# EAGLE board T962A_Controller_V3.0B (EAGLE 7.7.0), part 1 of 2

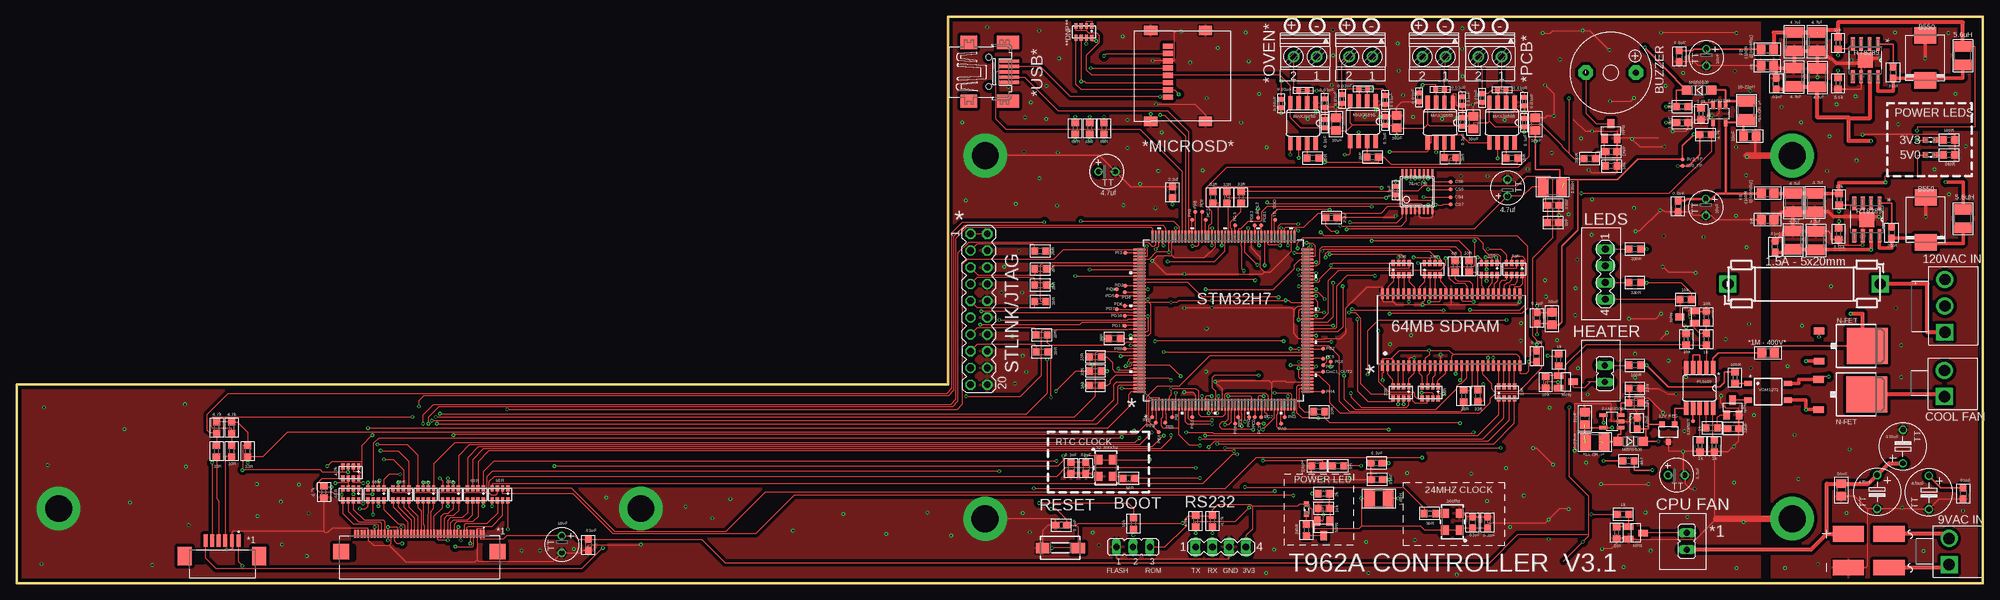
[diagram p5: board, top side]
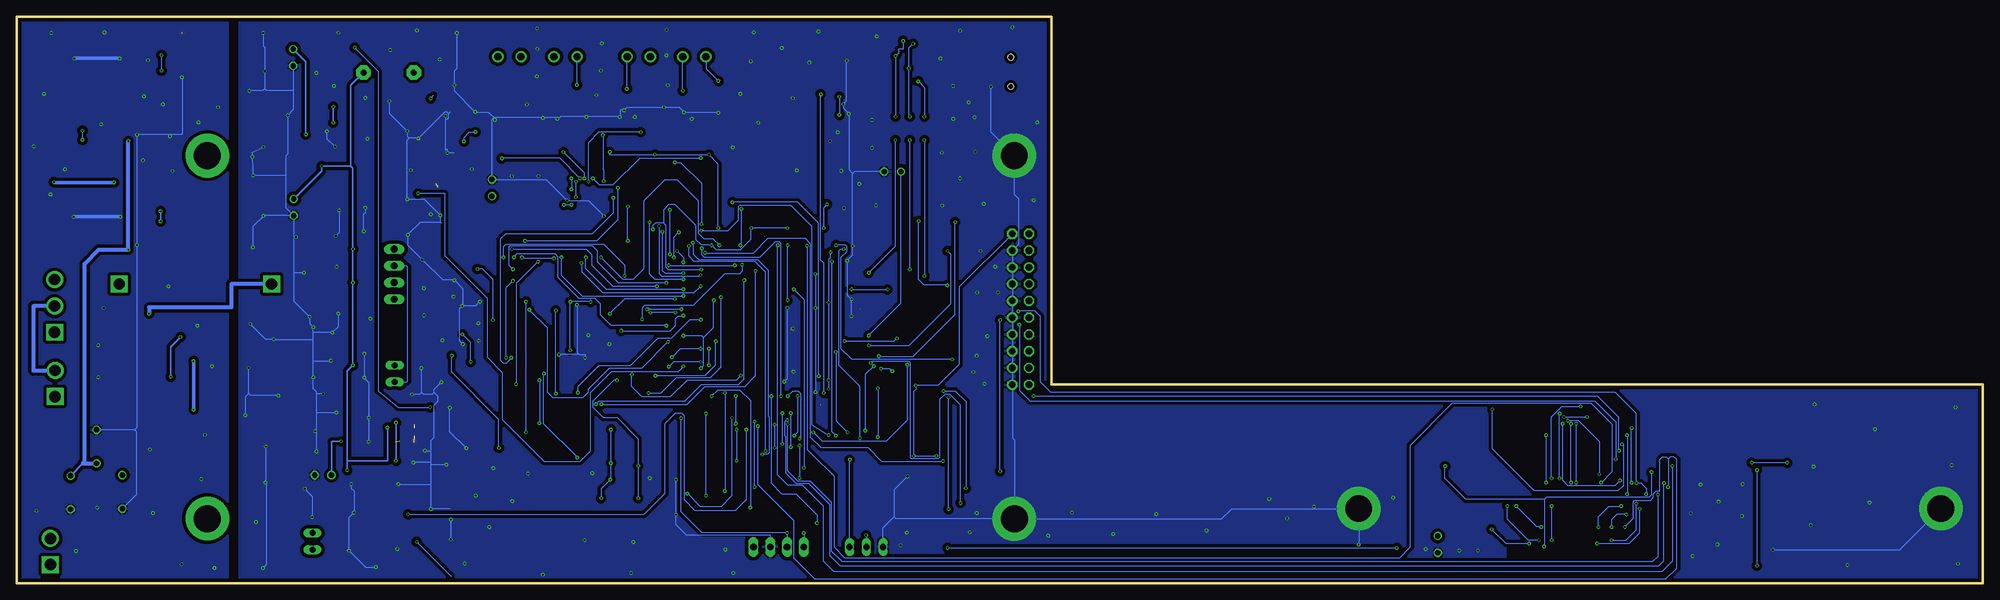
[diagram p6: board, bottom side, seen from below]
Size 297.71 x 85.85 mm. Coordinates in mm from the lower left corner, seen from the top.
Outline: 297.71,0 0,0 0,30.1 141,30.1 141,85.85 297.71,85.85 297.71,0
Copper layers (1*16): Top 0.035559375mm / dielectric 1.6mm / Bottom 0.035559375mm
Design rules "oshpark-2layer-tented": minimum track width 6mil, minimum drill 10mil, track to track 6mil, track to pad 6mil, pad to pad 6mil, via to via 6mil, smd to smd 6mil, copper to edge 15mil, drill to drill 6mil, minimum pad ring 5mil, minimum via ring 5mil, stop-mask expansion 2.5mil, vias tented up to drill 20mil, thermal gap 10mil

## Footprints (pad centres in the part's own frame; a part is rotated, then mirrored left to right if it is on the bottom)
Z4-D = smd 2.4 x 4.7: AC1 2.55,-3.1; AC2 -2.55,-3.1; VDD 2.55,3.1; VSS -2.55,3.1
TT5D7 = drill 0.813: + -2.54,0 | drill 0.813 octagon: - 2.54,0
C0603 = smd 1.1 x 1: 1 -0.85,0; 2 0.85,0
TT2D5 = drill 0.813: + -1.27,0 | drill 0.813 octagon: - 1.27,0
C0805 = smd 1.3 x 1.5: 1 -0.95,0; 2 0.95,0
C0402 = smd 0.7 x 0.9: 1 -0.65,0; 2 0.65,0
C1210 = smd 1.6 x 2.7: 1 -1.4,0; 2 1.4,0
SOD123 = smd 1.4 x 1.4: A -1.9,0; C 1.9,0
FUSE_HOLDER_5X20MM_1.78MM = drill 1.707 square: 1 -2.565,0; 2 20.498,0.025
SOT23-3 = smd 0.8 x 0.9: 1 -0.95,-1; 2 0.95,-1; 3 0,1.659
TSSOP16 = smd 0.305 x 0.991: 1 -2.275,-2.918; 2 -1.625,-2.918; 3 -0.975,-2.918; 4 -0.325,-2.918; 5 0.325,-2.918; 6 0.975,-2.918; 7 1.625,-2.918; 8 2.275,-2.918; 9 2.275,2.918; 10 1.625,2.918; 11 0.975,2.918; 12 0.325,2.918; 13 -0.325,2.918; 14 -0.975,2.918; 15 -1.625,2.918; 16 -2.275,2.918
MOLEX_54104-4031-REV = smd 0.3 x 1.2: 1 9.75,0.6; 2 9.25,0.6; 3 8.75,0.6; 4 8.25,0.6; 5 7.75,0.6; 6 7.25,0.6; 7 6.75,0.6; 8 6.25,0.6; 9 5.75,0.6; 10 5.25,0.6; 11 4.75,0.6; 12 4.25,0.6; 13 3.75,0.6; 14 3.25,0.6; 15 2.75,0.6; 16 2.25,0.6; 17 1.75,0.6; 18 1.25,0.6; 19 0.75,0.6; 20 0.25,0.6; 21 -0.25,0.6; 22 -0.75,0.6; 23 -1.25,0.6; 24 -1.75,0.6; 25 -2.25,0.6; 26 -2.75,0.6; 27 -3.25,0.6; 28 -3.75,0.6; 29 -4.25,0.6; 30 -4.75,0.6; 31 -5.25,0.6; 32 -5.75,0.6; 33 -6.25,0.6; 34 -6.75,0.6; 35 -7.25,0.6; 36 -7.75,0.6; 37 -8.25,0.6; 38 -8.75,0.6; 39 -9.25,0.6; 40 -9.75,0.6 | smd 2.4 x 2.4: FITTING_NAIL_1 -11.85,-2.1; FITTING_NAIL_2 11.85,-2.1
KK41791-4020_2-PIN = drill 1.707 square: 1 -1.981,0 | drill 1.707: 2 1.981,0
MOLEX_52271-0679_REV = smd 0.6 x 1.9: 1 2.5,3.5; 2 1.5,3.5; 3 0.5,3.5; 4 -0.5,3.5; 5 -1.5,3.5; 6 -2.5,3.5 | smd 2.1 x 2.8: FITTING_NAIL_1 -5.65,1.15; FITTING_NAIL_2 5.65,1.15
KK41791-4020_3-PIN = drill 1.707 square: 1 -1.981,0 | drill 1.707: 2 1.981,0; 3 5.994,0
JP2 = drill 0.914 long: 1 -2.54,0; 2 0,0; 3 2.54,0
JP1 = drill 0.914 long: 1 0,-1.27; 2 0,1.27
L0805 = smd 1.3 x 1.5: 1 -0.95,0; 2 0.95,0
R1210 = smd 1.6 x 2.7: 1 -1.4,0; 2 1.4,0
SML0603 = smd 0.8 x 0.8: A 0.75,0; C -0.75,0
R0603 = smd 1 x 1.1: 1 -0.85,0; 2 0.85,0
R0805 = smd 1.3 x 1.5: 1 -0.95,0; 2 0.95,0
742-8NS-REV = smd 0.5 x 0.9: 1 1.2,-0.9; 2 0.4,-0.9; 3 -0.4,-0.9; 4 -1.2,-0.9; 5 -1.2,0.9; 6 -0.4,0.9; 7 0.4,0.9; 8 1.2,0.9
742-8NS = smd 0.5 x 0.9: 1 -1.2,-0.9; 2 -0.4,-0.9; 3 0.4,-0.9; 4 1.2,-0.9; 5 1.2,0.9; 6 0.4,0.9; 7 -0.4,0.9; 8 -1.2,0.9
DTSM-3 = smd 2 x 1.6: 1 -2.7,0; 2 2.7,0
YHE12-XX-7.6MM = drill 0.914 pad 2.159 octagon: + 3.81,0.025; - -3.81,0.025
MA10-2 = drill 1.016 octagon: 1 -11.43,-1.27; 2 -11.43,1.27; 3 -8.89,-1.27; 4 -8.89,1.27; 5 -6.35,-1.27; 6 -6.35,1.27; 7 -3.81,-1.27; 8 -3.81,1.27; 9 -1.27,-1.27; 10 -1.27,1.27; 11 1.27,-1.27; 12 1.27,1.27; 13 3.81,-1.27; 14 3.81,1.27; 15 6.35,-1.27; 16 6.35,1.27; 17 8.89,-1.27; 18 8.89,1.27; 19 11.43,-1.27; 20 11.43,1.27
MA04-1 = drill 1.016 long: 1 -3.81,0; 2 -1.27,0; 3 1.27,0; 4 3.81,0
SOT23-BEC = smd 1 x 1.4: B -0.95,-1.1; C 0,1.1; E 0.95,-1.1
TP06R = smd 0.6 x 0.6: TP 0,0
LQFP176-24X24MM-M = smd 1.778 x 0.279: 1 -12.725,10.75; 2 -12.725,10.25; 3 -12.725,9.75; 4 -12.725,9.25; 5 -12.725,8.75; 6 -12.725,8.25; 7 -12.725,7.75; 8 -12.725,7.25; 9 -12.725,6.75; 10 -12.725,6.25; 11 -12.725,5.75; 12 -12.725,5.25; 13 -12.725,4.75; 14 -12.725,4.25; 15 -12.725,3.75; 16 -12.725,3.25; 17 -12.725,2.75; 18 -12.725,2.25; 19 -12.725,1.75; 20 -12.725,1.25; 21 -12.725,0.75; 22 -12.725,0.25; 23 -12.725,-0.25; 24 -12.725,-0.75; 25 -12.725,-1.25; 26 -12.725,-1.75; 27 -12.725,-2.25; 28 -12.725,-2.75; 29 -12.725,-3.25; 30 -12.725,-3.75; 31 -12.725,-4.25; 32 -12.725,-4.75; 33 -12.725,-5.25; 34 -12.725,-5.75; 35 -12.725,-6.25; 36 -12.725,-6.75; 37 -12.725,-7.25; 38 -12.725,-7.75; 39 -12.725,-8.25; 40 -12.725,-8.75; 41 -12.725,-9.25; 42 -12.725,-9.75; 43 -12.725,-10.25; 44 -12.725,-10.75; 89 12.725,-10.75; 90 12.725,-10.25; 91 12.725,-9.75; 92 12.725,-9.25; 93 12.725,-8.75; 94 12.725,-8.25; 95 12.725,-7.75; 96 12.725,-7.25; 97 12.725,-6.75; 98 12.725,-6.25; 99 12.725,-5.75; 100 12.725,-5.25; 101 12.725,-4.75; 102 12.725,-4.25; 103 12.725,-3.75; 104 12.725,-3.25; 105 12.725,-2.75; 106 12.725,-2.25; 107 12.725,-1.75; 108 12.725,-1.25; 109 12.725,-0.75; 110 12.725,-0.25; 111 12.725,0.25; 112 12.725,0.75; 113 12.725,1.25; 114 12.725,1.75; 115 12.725,2.25; 116 12.725,2.75; 117 12.725,3.25; 118 12.725,3.75; 119 12.725,4.25; 120 12.725,4.75; 121 12.725,5.25; 122 12.725,5.75; 123 12.725,6.25; 124 12.725,6.75; 125 12.725,7.25; 126 12.725,7.75; 127 12.725,8.25; 128 12.725,8.75; 129 12.725,9.25; 130 12.725,9.75; 131 12.725,10.25; 132 12.725,10.75 | smd 0.279 x 1.778: 45 -10.75,-12.725; 46 -10.25,-12.725; 47 -9.75,-12.725; 48 -9.25,-12.725; 49 -8.75,-12.725; 50 -8.25,-12.725; 51 -7.75,-12.725; 52 -7.25,-12.725; 53 -6.75,-12.725; 54 -6.25,-12.725; 55 -5.75,-12.725; 56 -5.25,-12.725; 57 -4.75,-12.725; 58 -4.25,-12.725; 59 -3.75,-12.725; 60 -3.25,-12.725; 61 -2.75,-12.725; 62 -2.25,-12.725; 63 -1.75,-12.725; 64 -1.25,-12.725; 65 -0.75,-12.725; 66 -0.25,-12.725; 67 0.25,-12.725; 68 0.75,-12.725; 69 1.25,-12.725; 70 1.75,-12.725; 71 2.25,-12.725; 72 2.75,-12.725; 73 3.25,-12.725; 74 3.75,-12.725; 75 4.25,-12.725; 76 4.75,-12.725; 77 5.25,-12.725; 78 5.75,-12.725; 79 6.25,-12.725; 80 6.75,-12.725; 81 7.25,-12.725; 82 7.75,-12.725; 83 8.25,-12.725; 84 8.75,-12.725; 85 9.25,-12.725; 86 9.75,-12.725; 87 10.25,-12.725; 88 10.75,-12.725; 133 10.75,12.725; 134 10.25,12.725; 135 9.75,12.725; 136 9.25,12.725; 137 8.75,12.725; 138 8.25,12.725; 139 7.75,12.725; 140 7.25,12.725; 141 6.75,12.725; 142 6.25,12.725; 143 5.75,12.725; 144 5.25,12.725; 145 4.75,12.725; 146 4.25,12.725; 147 3.75,12.725; 148 3.25,12.725; 149 2.75,12.725; 150 2.25,12.725; 151 1.75,12.725; 152 1.25,12.725; 153 0.75,12.725; 154 0.25,12.725; 155 -0.25,12.725; 156 -0.75,12.725; 157 -1.25,12.725; 158 -1.75,12.725; 159 -2.25,12.725; 160 -2.75,12.725; 161 -3.25,12.725; 162 -3.75,12.725; 163 -4.25,12.725; 164 -4.75,12.725; 165 -5.25,12.725; 166 -5.75,12.725; 167 -6.25,12.725; 168 -6.75,12.725; 169 -7.25,12.725; 170 -7.75,12.725; 171 -8.25,12.725; 172 -8.75,12.725; 173 -9.25,12.725; 174 -9.75,12.725; 175 -10.25,12.725; 176 -10.75,12.725
SOT23-5L = smd 0.55 x 1.2: 1 -0.95,-1.3; 2 0,-1.3; 3 0.95,-1.3; 4 0.95,1.3; 5 -0.95,1.3
SO08 = smd 0.66 x 2.032: 1 -1.905,-3.073; 2 -0.635,-3.073; 3 0.635,-3.073; 4 1.905,-3.073; 5 1.905,3.073; 6 0.635,3.073; 7 -0.635,3.073; 8 -1.905,3.073
SOIC127P600X175-9N = smd 1.981 x 0.559: 1 -2.464,1.905; 2 -2.464,0.635; 3 -2.464,-0.635; 4 -2.464,-1.905; 5 2.464,-1.905; 6 2.464,-0.635; 7 2.464,0.635; 8 2.464,1.905 | smd 2.286 x 2.286: 9 0,0
DO214AB-SMC = smd 2.5 x 3.3: A 3.4,0; C -3.4,0
SOP10 = smd 0.66 x 2.032: 1 -2.057,-3.073; 2 -1.041,-3.073; 3 -0.025,-3.073; 4 0.991,-3.073; 5 2.007,-3.073; 6 2.007,3.073; 7 0.991,3.073; 8 -0.025,3.073; 9 -1.041,3.073; 10 -2.057,3.073
DPACK_3 = smd 1 x 1.6: 1 -2.28,-4.8; 3 2.28,-4.8 | smd 5.4 x 6.2: 4 0,2.5
SOP04 = smd 0.8 x 1.2: 1 -1.27,-3; 2 1.27,-3; 3 1.27,3; 4 -1.27,3
TSOP54 = smd 0.4 x 1.6: 1 -10.4,-5.45; 2 -9.6,-5.45; 3 -8.8,-5.45; 4 -8,-5.45; 5 -7.2,-5.45; 6 -6.4,-5.45; 7 -5.6,-5.45; 8 -4.8,-5.45; 9 -4,-5.45; 10 -3.2,-5.45; 11 -2.4,-5.45; 12 -1.6,-5.45; 13 -0.8,-5.45; 14 0,-5.45; 15 0.8,-5.45; 16 1.6,-5.45; 17 2.4,-5.45; 18 3.2,-5.45; 19 4,-5.45; 20 4.8,-5.45; 21 5.6,-5.45; 22 6.4,-5.45; 23 7.2,-5.45; 24 8,-5.45; 25 8.8,-5.45; 26 9.6,-5.45; 27 10.4,-5.45; 28 10.4,5.45; 29 9.6,5.45; 30 8.8,5.45; 31 8,5.45; 32 7.2,5.45; 33 6.4,5.45; 34 5.6,5.45; 35 4.8,5.45; 36 4,5.45; 37 3.2,5.45; 38 2.4,5.45; 39 1.6,5.45; 40 0.8,5.45; 41 0,5.45; 42 -0.8,5.45; 43 -1.6,5.45; 44 -2.4,5.45; 45 -3.2,5.45; 46 -4,5.45; 47 -4.8,5.45; 48 -5.6,5.45; 49 -6.4,5.45; 50 -7.2,5.45; 51 -8,5.45; 52 -8.8,5.45; 53 -9.6,5.45; 54 -10.4,5.45
MOLEX:47219-2001 = smd 1.45 x 2: G1 13.75,0; G2 13.75,8.3; G3 0,8.3; G4 0,0 | smd 0.8 x 1.5: P1 10.08,2.6; P2 8.98,2.6; P3 7.88,2.6; P4 6.78,2.6; P5 5.68,2.6; P6 4.58,2.6; P7 3.48,2.6; P8 2.38,2.6
1751248 = drill 1.1 pad 1.7: 1 -1.75,-0.1; 2 1.75,-0.1
32005-201 = smd 3.1 x 0.5: 1 3,1.6; 2 3,0.8; 3 3,0; 4 3,-0.8; 5 3,-1.6 | smd 2.5 x 2: M1 -3,-4.45; M2 -3,4.45 | smd 3.3 x 2: M3 2.9,4.45; M4 2.9,-4.45 | hole 0.9: 0,2.2; 0,-2.2
OSCILLATOR-SMD-5X3.2 = smd 1.397 x 1.194: 1 -1.27,-1.1; 2 1.27,-1.1; 3 1.27,1.1; 4 -1.27,1.1

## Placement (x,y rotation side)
B1  Z4DGP406L-HF  [Z4-D]  280.39,4.93 90 top
C1  470uF  [TT5D7]  289.53,13.74 270 top
C2  0.1uF  [C0603]  205.89,18.21 180 top
C3  10uF  [TT2D5]  255.83,79.65 270 top
C4  0.01uF  [C0603]  205.97,15.72 180 top
C5  .1uf  [C0603]  158.17,8.79 180 top
C6  470uF  [TT5D7]  281.69,13.84 270 top
C7  10uF  [C0805]  276.28,14.12 270 top
C8  0.1uF  [C0603]  222.71,9.22 90 top
C9  2.2uF  [C0603]  175.01,59.23 90 top
C10  2.2uF  [C0603]  199.09,55.37 0 top
C11  10uF  [TT2D5]  255.75,56.95 270 top
C12  0.01uF  [C0603]  220.42,9.22 90 top
C13  .1uf  [C0603]  230.2,40.18 90 top
C14  .1uf  [C0603]  230.15,34.39 90 top
C15  1.0uF  [C0603]  252.17,69.77 0 top
C16  0.1uF  [C0603]  251.71,79.83 270 top
C17  0.1uF  [C0603]  251.54,57.1 270 top
C18  10uF  [C0805]  262.41,67.72 0 top
C19  0.01uF  [C0402]  203.89,74.9 180 top
C20  0.01uF  [C0402]  200.66,73.36 90 top
C21  0.01uF  [C0402]  207.19,73.2 90 top
C22  0.01uF  [C0402]  215.52,74.8 180 top
C23  0.01uF  [C0402]  212.37,73.61 90 top
C24  0.1uF  [C0603]  159.64,17.48 270 top
C25  0.01uF  [C0603]  161.9,17.48 270 top
C26  0.1uF  [C0603]  232.61,54.64 0 top
C27  22nf  [C0603]  259.89,23.44 180 top
C28  470uF  [TT5D7]  285.6,20.7 90 top
C29  0.01uF  [C0603]  232.66,57.28 0 top
C30  1.0uF  [C0603]  245.34,24.23 90 top
C31  0.1uF  [C0402]  208.79,59.49 270 top
C32  0.1uF  [C0402]  207.21,70.03 270 top
C33  0.1uF  [C0402]  218.87,69.88 270 top
C34  10uF  [C0805]  237.44,24.99 90 top
C35  0.1uF  [C0402]  228.24,69.77 270 top
C36  0.1uF  [C0402]  198.07,69.62 270 top
C37  4.7uF  [TT2D5]  251.31,16.38 0 top
C38  4.7uF  [TT2D5]  165.07,62.36 0 top
C39  4.7uF  [TT2D5]  225.73,59.89 90 top
C40  10uF  [TT2D5]  82.55,5.89 270 top
C41  .01uF  [C0603]  86.56,5.82 270 top
C42  10uF  [C0805]  232.46,40.08 90 top
C45  DNP  [C0603]  241.43,65.38 180 top
C46  10uF  [C0805]  199.72,69.55 270 top
C47  10uF  [C0805]  208.94,69.9 270 top
C48  0.01uF  [C0402]  191.44,72.67 90 top
C49  10uF  [C0805]  220.55,69.77 270 top
C50  .01uF  [C0603]  294.72,13.61 270 top
C51  10uF  [C0805]  229.97,69.55 270 top
C52  0.01uF  [C0402]  198.04,72.75 90 top
C53  0.01uF  [C0402]  194.77,74.63 180 top
C54  .01uF  [C0603]  284.1,77.37 270 top
C55  .01uF  [C0603]  266.4,75.69 90 top
C56  4.7uF  [C1210]  272.64,76.58 90 top
C57  4.7uF  [C1210]  269.09,76.66 90 top
C58  47uf  [C1210]  269.14,82.02 270 top
C59  47uf  [C1210]  272.59,82.02 270 top
C60  0.01uF  [C0402]  218.85,73.03 90 top
C61  0.01uF  [C0402]  224.89,74.73 180 top
C62  0.01uF  [C0402]  221.89,73.51 90 top
C63  0.01uF  [C0402]  228.24,72.95 90 top
C88  .01uF  [C0603]  283.87,53.11 270 top
C89  .01uF  [C0603]  266.24,50.98 90 top
C90  4.7uF  [C1210]  272.41,51.92 90 top
C91  4.7uF  [C1210]  268.94,51.99 90 top
C92  47uf  [C1210]  272.29,57.68 270 top
C93  47uf  [C1210]  269.01,57.63 270 top
D1  MBR0520LT  [SOD123]  254.71,74.68 180 top
D2  MBR0520LT  [SOD123]  244.35,21.49 0 top
F1  FUSE  [FUSE_HOLDER_5X20MM_1.78MM]  261.67,45.31 0 top
IC1  TLV760SOT-23-3  [SOT23-3]  250.09,23.06 180 top
IC2  74138TSSOP  [TSSOP16]  212.06,59.31 0 top
J1  54104-4031MOLEX_54101_4031-REV  [MOLEX_54104-4031-REV]  60.99,6.91 0 top
J2  0026604020  [KK41791-4020_2-PIN]  292.58,4.8 90 top
J3  52271-0679_REVMOLEX_52271-0679-REV  [MOLEX_52271-0679_REV]  31.11,2.95 0 top
J4  0026604030  [KK41791-4020_3-PIN]  291.95,40.01 90 top
J5  0026604020  [KK41791-4020_2-PIN]  291.87,30.25 90 top
JP1  [JP2]  169.04,5.49 0 top
JP2  [JP1]  240.46,31.75 0 top
JP3  [JP1]  252.88,6.35 180 top
L1  100R@100Mhz  [L0805]  265.1,59.11 180 top
L2  5.6uH  [R1210]  294.67,79.91 90 top
L3  5.6uH  [R1210]  294.69,55.22 90 top
L4  10uH  [R1210]  206.27,12.85 0 top
L6  100R@100Mhz  [L0805]  265.07,80.92 180 top
L8  10uH  [R1210]  232.54,60.02 180 top
LED1  [SML0603]  289.74,67.16 180 top
LED2  [SML0603]  195.3,11.23 90 top
LED5  [SML0603]  289.71,64.87 180 top
R1  20R  [R0603]  154.99,50.32 180 top
R2  100R  [R0603]  292.56,67.16 0 top
R3  20R  [R0603]  155.02,47.62 180 top
R4  20R  [R0603]  155.02,45.16 180 top
R5  240R  [R0603]  292.58,64.87 180 top
R6  0R  [R0805]  265.1,55.12 180 top
R7  20R  [R0603]  154.99,42.7 180 top
R8  20R  [R0603]  155.19,37.62 180 top
R9  20R  [R0603]  155.24,35.05 180 top
R10  10k  [R0603]  163.35,29.97 0 top
R11  10k  [R0603]  169.09,9.04 90 top
R12  33R  [R0603]  219.94,48.03 270 top
R13  50R  [R0603]  168.4,15.88 180 top
R14  50R  [R0603]  213.97,10.57 0 top
R15  0R  [R0603]  217.78,48.03 270 top
R16  33R  [R0603]  181.13,58.45 90 top
R17  20R  [R0603]  205.33,64.54 180 top
R18  20R  [R0603]  217.04,64.47 180 top
R19  20R  [R0603]  226.39,64.39 180 top
R20  1k  [R0603]  256.67,23.52 0 top
R21  10k  [R0603]  252.78,36.98 90 top
R22  100R  [R0603]  245.01,33.02 180 top
R23  4.7k  [R0603]  178.51,9.4 270 top
R24  4.7k  [R0603]  181.05,9.4 270 top
R25  100R  [R0603]  260.17,31.14 90 top
R26  2.0k  [R0603]  245.01,29.51 0 top
R27  20R  [R0603]  196.27,64.41 180 top
R28  2k  [R0603]  197.92,13.59 180 top
R29  240R  [R0603]  195.3,8.08 270 top
R30  10k  [R0603]  197.92,11.35 0 top
R31  10K  [R0603]  275.77,81.81 270 top
R32  5.6k  [R0603]  275.77,75.69 270 top
R33  10K  [R0603]  275.92,58.17 270 top
R34  3.16k  [R0603]  275.84,52.91 270 top
R35  10k  [R0603]  241.45,63.22 180 top
R36  4k7  [R0603]  32.59,23.6 90 top
R37  4K7  [R0603]  255.7,67.97 0 top
R38  4k7  [R0603]  46.56,13.84 270 top
R39  0R  [R0805]  265.07,78.41 180 top
R40  1M  [R0805]  265.18,34.9 0 top
R41  4k7  [R0603]  30.3,23.6 90 top
R42  33R  [R0603]  221.23,28.4 90 top
R43  390R  [R0603]  238.18,64.34 180 top
R44  10k  [R0603]  255.83,40.34 90 top
R45  120k  [R0603]  252.17,72.21 180 top
R46  4K7  [R0603]  244.04,18.54 180 top
R47  80k  [R0603]  245.01,27.3 0 top
R48  68R  [R0603]  164.64,68.91 90 top
R49  68R  [R0603]  162.48,68.91 90 top
R50  68R  [R0603]  160.27,68.91 90 top
R51  33R  [R0603]  32.59,20.04 270 top
R52  1k  [R0603]  243.2,10.44 0 top
R53  10k  [R0603]  242.24,7.65 90 top
R54  1k  [R0603]  233.48,33.83 270 top
R55  10k  [R0603]  231.5,30.45 90 top
R56  330R  [R0603]  245.01,50.62 180 top
R57  330R  [R0603]  245.01,45.54 180 top
R58  10k  [R0603]  252.7,42.98 0 top
R59  0R  [R0603]  200.08,17.78 0 top
R60  DNP  [R0603]  196.93,17.78 0 top
R61  2.0k  [R0603]  255.04,71.07 270 top
R62  1k  [R0603]  254.86,20.8 90 top
R63  1k  [R0603]  257.02,20.8 90 top
R64  1k  [R0603]  255.83,36.98 90 top
R65  33R  [R0603]  30.28,20.04 270 top
R66  4k7  [R0603]  35,20.04 90 top
R67  33R  [R0603]  219.07,28.37 90 top
R68  33R  [R0603]  166.22,37.08 180 top
R69  33R  [R0603]  197.21,25.98 0 top
R70  33R  [R0603]  163.35,34.29 180 top
R71  33R  [R0603]  163.35,32.13 180 top
R72  33R  [R0603]  183.26,58.45 90 top
R73  33R  [R0603]  185.39,58.45 90 top
RN1  33R  [742-8NS-REV]  209.63,47.57 0 top
RN2  33R  [742-8NS-REV]  214.35,47.57 0 top
RN3  33R  [742-8NS-REV]  214.02,28.91 180 top
RN4  33R  [742-8NS-REV]  209.6,28.91 180 top
RN5  33R  [742-8NS]  225.6,28.91 0 top
RN6  4.7k  [742-8NS]  50.6,16.79 180 top
RN7  33R  [742-8NS]  226.75,47.57 180 top
RN8  33R  [742-8NS]  222.96,47.57 180 top
RN11  **DNP**  [742-8NS]  161.59,83.52 180 top
RN12  68R  [742-8NS-REV]  73.2,13.46 180 top
RN13  68R  [742-8NS-REV]  69.47,13.46 180 top
RN14  68R  [742-8NS-REV]  65.71,13.46 180 top
RN15  68R  [742-8NS-REV]  61.95,13.46 180 top
RN16  68R  [742-8NS-REV]  58.19,13.46 180 top
RN17  68R  [742-8NS-REV]  54.41,13.46 180 top
RN18  68R  [742-8NS-REV]  50.6,13.46 180 top
S1  DTSM-3  [DTSM-3]  158.04,5.36 0 top
SG1  YHE12-XX7.6MM  [YHE12-XX-7.6MM]  241.38,77.34 0 top
SV1  [MA10-2]  145.69,41.5 270 top
SV3  [MA04-1]  240.54,46.81 270 top
SV5  RS232  [MA04-1]  182.32,5.49 0 top
T1  BC817-16LT1SMD  [SOT23-BEC]  241.38,68.5 0 top
T3  BC817-16LT1SMD  [SOT23-BEC]  197.89,8.33 180 top
T4  BC817-16LT1SMD  [SOT23-BEC]  245.16,7.62 270 top
T5  BC817-16LT1SMD  [SOT23-BEC]  234.57,30.51 270 top
T6  BC817-16LT1SMD  [SOT23-BEC]  259.82,26.62 0 top
T7  BC817-16LT1SMD  [SOT23-BEC]  252.93,40.34 90 top
TP1  TPTP06R  [TP06R]  187.48,25.17 0 top
TP2  TPTP06R  [TP06R]  187.99,24.16 0 top
TP3  TPTP06R  [TP06R]  198.93,33.53 0 top
TP4  TPTP06R  [TP06R]  252.22,64.21 0 top
TP5  TPTP06R  [TP06R]  188.47,25.17 0 top
TP6  TPTP06R  [TP06R]  217.12,57.4 0 top
TP7  TPTP06R  [TP06R]  217.12,60.83 0 top
TP8  TPTP06R  [TP06R]  217.12,59.66 0 top
TP9  TPTP06R  [TP06R]  217.12,58.5 0 top
TP10  TPTP06R  [TP06R]  197.79,34.04 90 top
TP11  TPTP06R  [TP06R]  167.77,42.01 0 top
TP12  TPTP06R  [TP06R]  166.55,41.53 0 top
TP14  TPTP06R  [TP06R]  173.94,24.31 0 top
TP15  TPTP06R  [TP06R]  171.96,25.17 0 top
TP16  TPTP06R  [TP06R]  179.5,56.29 90 top
TP17  TPTP06R  [TP06R]  180.04,55.02 90 top
TP18  TPTP06R  [TP06R]  197.79,32.03 0 top
TP19  TPTP06R  [TP06R]  197.79,33.02 0 top
TP20  TPTP06R  [TP06R]  178.46,56.29 0 top
TP21  TPTP06R  [TP06R]  177.98,55.02 0 top
TP22  TPTP06R  [TP06R]  197.79,35.51 0 top
TP23  TPTP06R  [TP06R]  167.77,35.53 0 top
TP24  TPTP06R  [TP06R]  167.82,45.03 0 top
TP25  TPTP06R  [TP06R]  166.55,44.53 0 top
TP26  TPTP06R  [TP06R]  167.77,39.04 0 top
TP27  TPTP06R  [TP06R]  252.22,63.2 0 top
TP28  TPTP06R  [TP06R]  253.8,24.54 0 top
TP29  TPTP06R  [TP06R]  191.47,24.16 0 top
TP30  TPTP06R  [TP06R]  191.99,25.17 0 top
TP31  TPTP06R  [TP06R]  167.77,44.04 0 top
TP32  TPTP06R  [TP06R]  166.55,43.56 0 top
TP33  TPTP06R  [TP06R]  184.48,24.16 0 top
TP34  TPTP06R  [TP06R]  184.96,25.17 0 top
TP35  TPTP06R  [TP06R]  167.77,40.54 0 top
TP36  TPTP06R  [TP06R]  197.79,29.03 0 top
TP39  TPTP06R  [TP06R]  184.48,54.23 0 top
TP40  TPTP06R  [TP06R]  167.82,50.04 0 top
TP41  TPTP06R  [TP06R]  174.98,25.17 0 top
TP42  TPTP06R  [TP06R]  188.47,54.23 0 top
TP43  TPTP06R  [TP06R]  187.96,55.37 0 top
TP44  TPTP06R  [TP06R]  187.48,54.23 0 top
TP45  TPTP06R  [TP06R]  177.98,25.17 0 top
TP46  TPTP06R  [TP06R]  190.55,55.02 0 top
TP47  TPTP06R  [TP06R]  186.61,25.17 0 top
TP48  TPTP06R  [TP06R]  172.47,24.31 0 top
TP49  TPTP06R  [TP06R]  172.95,22.89 0 top
U1  STM32H7X3IITLQFP176-24X24MM-M  [LQFP176-24X24MM-M]  182.73,39.78 90 top
U$1  FAN5333ABSOT23-5  [SOT23-5L]  257.81,71.15 180 top
U$2  INDUCTOR-GENERIC1210-PKG  [R1210]  261.9,71.63 90 top
U$3  MAX31855  [SO08]  194.77,69.7 180 top
U$4  MAX31855  [SO08]  203.83,69.98 180 top
U$5  MAX31855  [SO08]  215.54,69.8 180 top
U$6  MAX31855  [SO08]  224.89,69.8 180 top
U$7  RT8289  [SOIC127P600X175-9N]  279.91,79.22 270 top
U$8  DIODE-SMC  [DO214AB-SMC]  288.98,79.58 90 top
U$9  RT8289  [SOIC127P600X175-9N]  280.14,55.09 270 top
U$10  FL5160SOP10  [SOP10]  254.79,29.57 180 top
U$11  N-PWR-MOSFETDPAK3  [DPACK_3]  277.65,28.6 270 top
U$12  N-PWR-MOSFETDPAK3  [DPACK_3]  277.67,35.94 270 top
U$13  DIODE-SMC  [DO214AB-SMC]  289.05,55.07 90 top
U$14  VOM1271  [SOP04]  265.15,29.01 270 top
U$15  AS4C32M16SB  [TSOP54]  217.2,38.4 0 top
U$16  INDUCTOR-GENERIC1210-PKG  [R1210]  238.94,21.36 0 top
U$17  FAN5333ABSOT23-5  [SOT23-5L]  241.55,24.51 90 top
U$19  MOLEX-47219-2001  [MOLEX:47219-2001]  171.7,83.72 270 top
X1  1751248  [1751248]  195.1,79.68 180 top
X2  1751248  [1751248]  203.5,79.68 180 top
X3  1751248  [1751248]  214.6,79.68 180 top
X4  1751248  [1751248]  223.09,79.68 180 top
X5  MINI-USB-32005-201  [32005-201]  147.19,77.47 0 top
Y1  OSCILLATORSMD-5X3  [OSCILLATOR-SMD-5X3.2]  217.37,9.32 90 top
Y2  OSCILLATORSMD-5X3  [OSCILLATOR-SMD-5X3.2]  164.92,17.45 270 top

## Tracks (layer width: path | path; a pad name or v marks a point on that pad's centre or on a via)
3V3_VDD  (via drill 0.25 pad 0.51)  (1 unrouted)
  Top 0.152: L8.1 233.64,60.78 233.51,61.12 | 222.99,70.03 222.68,69.72 220.55,69.72 220.55,69.22 | C33.2 220.55,69.22 | 161.99,83.67 161.19,83.67 | 161.19,83.67 160.39,83.67 RN11.4 | 161.19,83.67 RN11.3 | 161.99,83.67 162.35,83.31 163.55,83.31 163.96,82.91 163.96,81.94 161.98,79.96 161.98,77.75 162.79,76.94 U$19.P4 191.26,76.94 192.86,75.34 U$3.4 192.86,70.56 194.45,68.97 C36.2 199.72,68.97 C46.2 201.44,68.59 202.23,69.39 | 208.1,33.98 207.01,33.98 | 207.01,33.98 206.71,33.98 206.71,32.95 U$15.1 | 49.4,16.82 v50.19,16.82 v50.2,16.82 RN6.3 RN6.2 51,16.94 51.8,16.94 RN6.1 | 49.4,16.82 46.38,16.82 46.05,17.14 v34.21,17.14 34.21,20.89 R66.2 35,22.84 33.39,24.45 R36.2 R41.2 | 203.58,8.66 203.28,8.36 196.29,8.36 196.09,8.56 196.09,11.19 LED2.A 194.23,11.98 193.92,11.66 187.1,11.66 | JP1.3 173.84,5.49 177.01,8.66 177.01,9.84 177.42,10.25 R23.1 R24.1 181.05,11.15 181.86,11.96 186.79,11.96 187.1,11.66 | 187.1,11.66 187.1,8.2 186.13,7.24 SV5.4 | 208.1,33.98 209.37,35.26 v213.87,35.26 | v213.87,35.26 216.89,35.26 217.5,34.65 | 222.99,70.03 223.89,69.12 C35.2 v228.24,68.35 | 202.23,69.39 207.21,69.39 C32.2 208.94,69.38 C47.2 | C33.2 | C33.2 213.97,69.22 213.66,69.53 | C47.2 213.09,68.95 213.66,69.53 | 203.58,8.66 v203.58,12.85 L4.1 | 220.55,69.22 C49.2 | C13.1 v230.2,37.69 | C14.1 228.97,33.54 v228.96,33.55 228.96,32.18 228.55,31.77 227.6,31.77 U$15.27 227.6,34.23 227.18,34.65 217.5,34.65 | 161.99,83.67 RN11.2 161.99,85.11 162.79,85.11 RN11.1 | 203.58,8.66 212.65,8.66 213.26,8.05 Y1.4 Y1.1 218.47,8.37 C12.1 C8.1 | v171.58,18.72 Y2.4 Y2.1 163.82,19.3 v161.9,19.3 C25.1 C24.1 | v34.21,2.64 33.62,3.24 J3.1
  Top 0.152: 213.66,69.53 213.66,72.26 213.64,72.29 U$5.4 | 202.23,69.39 201.93,69.7 U$4.4 | 222.99,70.03 U$6.4 | 49.4,16.82 RN6.4 | SV1.2 SV1.1 | IC2.16 209.79,61.32 209.38,60.91 v208.79,60.91 C31.1 | v66.42,5.54 69.03,5.54 69.24,5.74 J1.4 | v213.87,35.26 213.87,34.59 213.46,34.19 213.4,34.19 213.2,33.98 U$15.9 | 217.5,34.65 217.2,34.34 U$15.14 | 208.1,33.98 208.41,33.98 208.41,32.95 U$15.3 | v203.58,17.78 R59.2 | v213.87,42.65 215.44,42.65 215.6,42.8 U$15.43 | v158.45,19.3 158.45,18.54 157.63,17.73 v81.43,17.73 | 207.01,33.98 207.01,31.9 206.81,31.9 v206.81,30.73 | C47.2 v208.94,67.89 | v161.57,29.97 R10.1 | v210.79,42.65 v210.8,42.65 U$15.49
  Top 0.254: v253.92,67.97 252.22,66.27 TP4.TP 245.44,64.21 242.37,61.14 236.37,61.14 | C16.1 253.68,80.68 253.92,80.92 C3.+ L6.2 | 236.37,61.14 234.26,61.14 234.26,60.55 | C51.2 v229.97,66.93 229.97,62.64 233.64,62.64 233.64,60.78 | 236.37,61.14 236.37,53.52 233.92,51.07 233.92,39.55 233.51,39.13 C42.1 232.26,39.33 C13.1
  Bottom 0.152: v213.87,35.26 v213.87,42.65 v210.79,42.65 | v203.58,12.85 v203.58,17.78 203.58,21.89 206.78,25.09 208.89,25.09 210.49,26.69 210.49,27.56 207.31,30.73 v206.81,30.73 | v50.19,16.82 50.19,13.41 50.6,13.01 66.12,13.01 66.42,12.7 | v158.45,19.3 v161.9,19.3 161.9,29.03 161.57,29.36 v161.57,29.97 158.17,29.97 154.99,33.15 154.99,44.91 SV1.2 | v228.96,33.55 228.96,36.45 v230.2,37.69 | JP1.3 v171.58,18.72 | v34.21,17.14 v34.21,2.64 | 66.42,12.7 v66.42,5.54 | 66.42,12.7 78.27,12.7 81.44,15.88 v81.44,17.72 v81.43,17.73 | v208.79,60.91 | v208.79,60.91 208.79,62.59 208.94,62.74 v208.94,67.89 | v229.97,66.93 229.97,67.54 229.16,68.35 v228.24,68.35
  Bottom 0.254: C3.+ 253.92,79.02 v253.92,67.97
5V0_VDD  (via drill 0.25 pad 0.51)  (2 unrouted)
  Top 0.152: v246.79,45.54 251.94,45.54 253.55,43.93 R58.2 | U$17.5 240.26,23.57 | 238.23,23.56 237.46,23.56
  Top 0.203: R57.1 v246.79,45.54 | v246.79,50.62 R56.1 | v246.79,33.02 R22.1
  Top 0.254: v251.51,63.2 TP27.TP 253.11,63.2 254.85,64.94 R37.1 | v246.79,33.02 250.09,29.72 257.84,29.72 258.55,30.43 258.55,32 258.56,31.99 R25.2 | v247.65,17.12 244.89,17.12 R46.1 | U$17.5 238.23,23.56 | 240.26,23.57 v241.55,23.57 | 237.46,23.56 237.46,22.33
  Top 0.305: L1.2 264.1,59.06 | U$1.5 261.52,69.84 arc90 U$2.1 | 238,21.36 U$16.1
  Top 0.406: C17.1 252.59,57.95 252.86,58.22 C11.+ 256.59,58.22 257.43,59.06 258.76,59.06 | 264.1,59.06 258.76,59.06 | U$1.5 258.76,59.06 | 261.52,69.84 261.46,69.84 C18.1
  Bottom 0.203: 247.09,63.2 247.09,75.46 SG1.+
  Bottom 0.254: C11.+ 251.51,62.46 v251.51,63.2 247.09,63.2 246.79,62.89 v246.79,50.62 v246.79,45.54 v246.79,33.02 247.65,32.16 247.65,18.52 | 247.65,18.52 v247.65,17.12 | v241.55,23.57 241.55,18.52 247.65,18.52
12V0_VDD
  Top 0.203: IC1.1 251.04,26.49 U$10.6
!CS0  (via drill 0.25 pad 0.51)
  Top 0.152: v194.13,64.41 U$3.6 | v210.44,61.32 | v210.44,61.32 IC2.15
  Bottom 0.152: v210.44,61.32 209.5,60.38 207.37,60.38 203.33,64.41 v194.13,64.41
!CS1  (via drill 0.25 pad 0.51)
  Top 0.152: v203.2,68.33 U$4.6 | v211.1,60.83 211.09,60.84 IC2.14
  Bottom 0.152: v211.1,60.83 211.1,66.78 209.5,68.38 203.25,68.38 v203.2,68.33
!CS2  (via drill 0.25 pad 0.51)
  Top 0.152: v214.91,65.3 U$5.6 | v211.73,61.32 v211.74,61.32 IC2.13
  Bottom 0.152: v211.73,61.32 211.73,62.13 v214.91,65.3
!CS3  (via drill 0.25 pad 0.51)
  Top 0.152: v224.26,64.36 U$6.6 | v212.39,61.32 IC2.12
  Bottom 0.152: v212.39,61.32 215.44,64.36 v224.26,64.36
!CS4  (via drill 0.25 pad 0.51)
  Top 0.152: v213.03,60.83 213.04,60.84 IC2.11 | v213.03,58.5 TP9.TP
  Bottom 0.152: v213.03,58.5 v213.03,60.83
!CS5  (via drill 0.25 pad 0.51)
  Top 0.152: v213.69,59.67 TP8.TP | v213.69,61.32 IC2.10
  Bottom 0.152: v213.69,61.32 v213.69,59.67
!CS6
  Top 0.152: IC2.9 214.34,61.24 214.75,60.83 TP7.TP
!CS7  (via drill 0.25 pad 0.51)
  Top 0.152: v214.83,57.3 215.93,57.3 216.03,57.4 TP6.TP | v213.69,57.3 IC2.7
  Bottom 0.152: v213.69,57.3 v214.83,57.3
!TP_INT  (via drill 0.25 pad 0.51)
  Top 0.152: v35,18.26 R66.1 37.31,19.19 41.06,22.94 169.04,22.94 v169.21,23.11 | v29.62,18.26 J3.5 | v167.92,32.89 168.68,32.89 168.88,33.1 168.88,33.53 U1.167
  Bottom 0.152: v29.62,18.26 v35,18.26 | v167.92,32.89 169.21,31.6 v169.21,23.11
A0  (via drill 0.25 pad 0.51)
  Top 0.152: v179.96,22.38 221.23,22.38 224.4,25.55 RN5.1 | v179.48,28.35 v179.48,28.34 U1.16
  Bottom 0.152: v179.48,28.35 179.48,22.86 v179.96,22.38
A1  (via drill 0.25 pad 0.51)
  Top 0.152: v179.17,21.89 222.03,21.89 225.2,25.07 RN5.2 | v180.95,28.35 180.13,28.35 179.98,28.19 U1.17
  Bottom 0.152: v180.95,28.35 180.16,29.13 179.4,29.13 178.99,28.73 178.99,22.07 v179.17,21.89
A2  (via drill 0.25 pad 0.51)
  Top 0.152: v180.49,20.62 181.46,21.59 222.83,21.59 226,24.77 RN5.3 | v180.47,25.76 180.48,25.77 U1.18
  Bottom 0.152: v180.47,25.76 180.49,25.73 v180.49,20.62
A3  (via drill 0.25 pad 0.51)  (1 unrouted)
  Top 0.152: v181.79,21.11 223.63,21.11 226.8,24.28 RN5.4 | v181.79,25.76 181.13,25.76 180.98,25.91 U1.19
  Bottom 0.152: v181.79,25.76 v181.79,21.11
A4  (via drill 0.25 pad 0.51)
  Top 0.152: v227.94,47.6 227.94,48.36 227.95,48.36 RN7.1 | v204.57,31.62 204.57,38.28 206.17,39.88 v225.58,39.88 | v188.04,31.47 181.38,31.47 180.98,31.06 180.98,29.67 181.48,29.16 U1.20
  Bottom 0.152: v225.58,39.88 225.58,46 227.18,47.6 v227.94,47.6 | v188.04,31.47 188.75,30.76 196.19,30.76 198.73,28.22 202.97,28.22 204.57,29.82 v204.57,31.62
A5  (via drill 0.25 pad 0.51)
  Top 0.152: v193.95,50.72 193.95,51.56 194.77,52.38 221.16,52.38 221.97,51.56 221.97,50.67 222.78,49.86 224.26,49.86 224.66,49.45 224.66,48.18 225.07,47.78 227.15,47.78 RN7.2 | v181.97,28.35 181.98,28.33 U1.21
  Bottom 0.152: v181.97,28.35 181.97,51.49 182.17,51.69 182.85,51.69 185.22,49.33 193.55,49.33 193.95,49.73 v193.95,50.72
A6  (via drill 0.25 pad 0.51)
  Top 0.152: v199.06,36.6 198.98,36.53 U1.60 | v220.09,41.43 227.63,41.43 228.45,42.24 228.45,49.07 228.04,49.48 226.55,49.48 226.35,49.28 RN7.3
  Bottom 0.152: v220.09,41.43 217.4,38.73 217.4,28.96 216.59,28.14 211.91,28.14 211.1,28.96 211.1,29.46 207.92,32.64 203.02,32.64 v199.06,36.6
A7  (via drill 0.25 pad 0.51)  (1 unrouted)
  Top 0.152: v200.79,45.01 200.79,38.84 199.97,38.03 U1.63 | v222.76,50.62 224.73,50.62 225.55,49.81 RN7.4
  Bottom 0.152: v222.76,50.62 211.5,50.62 210.68,49.81 210.68,48.2 207.49,45.01 v200.79,45.01
A8  (via drill 0.25 pad 0.51)
  Top 0.152: v205.66,46.58 201.4,46.58 199.8,44.98 199.8,38.73 199.59,38.53 U1.64 | v224,49.35 224.16,49.19 RN8.1
  Bottom 0.152: v224,49.35 224,51 223.6,51.41 208.84,51.41 205.66,48.23 v205.66,46.58
A9  (via drill 0.25 pad 0.51)
  Top 0.152: v222.43,49.38 223.16,49.38 223.36,49.17 RN8.2 | v199.31,39.01 199.3,39.03 U1.65
  Bottom 0.152: v199.31,39.01 207.71,39.01 209.31,40.62 209.31,42.33 210.11,43.13 212.55,43.13 215.72,46.3 215.72,49.43 216.13,49.84 221.97,49.84 v222.43,49.38
A10  (via drill 0.25 pad 0.51)
  Top 0.152: v222.55,47.55 v222.56,47.55 RN8.3 | v199.31,45.49 199.31,40.34 198.5,39.53 U1.66
  Bottom 0.152: v199.31,45.49 206.53,45.49 209.7,48.67 209.7,50.29 210.52,51.11 223.04,51.11 223.24,50.9 223.24,48.23 v222.55,47.55
A11  (via drill 0.25 pad 0.51)
  Top 0.152: v221.21,49.35 221.51,49.35 221.76,49.1 RN8.4 | v216.36,49.2 216.36,48.18 215.54,47.37 200.15,47.37 198.55,45.77 198.55,40.84 197.74,40.03 U1.67
  Bottom 0.152: v216.36,49.2 221.06,49.2 v221.21,49.35
A12  (via drill 0.25 pad 0.51)
  Top 0.152: v205.18,57.05 205.16,57.07 189.31,57.07 188.49,56.26 188.49,54.97 188.29,54.76 186.46,54.76 185.32,53.62 184.98,53.62 U1.106 | v205.18,51.89 218.34,51.89 219.94,50.29 R12.1
  Bottom 0.152: v205.18,51.89 v205.18,57.05
A13  (1 unrouted)
  Top 0.152: U1.107 TP39.TP
A14
  Top 0.152: U1.108 183.98,53.62 183.79,53.8 183.79,54.69 185.39,56.29 R73.1
A15
  Top 0.152: U1.109 183.48,57.59 R72.1
A16
  Top 0.152: U1.99 188.48,54.22 TP42.TP
A17  (via drill 0.25 pad 0.51)
  Top 0.152: v187.96,56.74 TP43.TP | v188.14,51.21 187.98,51.37 U1.100
  Bottom 0.152: v188.14,51.21 187.96,51.38 v187.96,56.74
A18
  Top 0.152: U1.101 TP44.TP | TP44.TP
A19
  Top 0.152: U1.2 172.48,25.69 172.49,25.68 172.49,24.33 TP48.TP
A20
  Top 0.152: TP49.TP 171.42,24.41 171.42,27.97 171.63,28.17 172.98,28.17 U1.3
A22
  Top 0.152: U1.5 173.98,25.71 174.01,25.68 174.01,24.38 TP14.TP
A23
  Top 0.152: TP15.TP 171.96,27.05 U1.1
A24
  Top 0.152: U1.156 167.78,39.03 TP26.TP
A_3V3  (via drill 0.25 pad 0.51)  (1 unrouted)
  Top 0.152: v287.73,68.56 287.73,69.09 296.44,69.09 296.44,81.31 L2.2 | v287.73,67.16 LED1.A
  Top 0.61: L2.2 294.67,84.96 275.77,84.96 275.77,83.8 | 275.77,83.8 R31.1 | 275.77,83.8 273.1,83.8 arc-90 272.72,83.42 C58.1 266.02,83.42 L6.1
  Bottom 0.152: v287.73,68.56 v287.73,67.16
A_5V0  (via drill 0.25 pad 0.51)
  Top 0.152: R33.1 275.92,59 | 272.81,59.02 272.75,59.08 C92.1 | C93.1 269.01,59.08 | v282.96,60.71 282.96,61.77 287.83,61.77 287.83,64.87 LED5.A
  Top 0.508: 272.81,59.02 R33.1 275.92,60.71 v282.96,60.71 | 269.01,59.08 C92.1 | L3.2 294.69,60.76 v292.05,60.76 | C93.1 266.12,59.03 L1.1
  Bottom 0.508: v292.05,60.76 arc-90 292,60.71 v282.96,60.71
AC_DC_IN  (via drill 0.25 pad 0.51)
  Top 0.152: v280.77,50.52 | C91.1 268.94,50.89
  Top 0.254: C1.+ 291.35,14.46 C50.1
  Top 0.406: 274.55,7.42 274.07,7.9 | 274.07,15.04 274.1,15.07
  Top 0.508: v280.77,50.52 C90.1 268.94,50.52 C91.1 268.47,50.13 C89.1 | v280.77,50.52 U$9.7 | C57.1 268.67,74.84 C55.1
  Top 0.61: B1.VDD 277.23,7.42 274.55,7.42 274.02,7.42 271.68,5.08 JP3.2 | C28.+ 283.46,18.16 C6.+ 280.38,15.07 C7.1 274.1,15.07 | 274.07,7.9 274.07,15.04 | v280.77,66.98 277.37,66.98 277.37,70.38 | 277.37,70.38 277.37,70.54 272.64,70.54 C56.1 269.09,75.18 C57.1 | U$7.7 280.54,70.38 277.37,70.38
  Bottom 0.254: C1.+ 287.66,18.16 287.4,18.42
  Bottom 0.61: 287.66,18.16 C28.+ | v280.77,66.98 v280.77,50.52 285.27,50.52 287.4,48.39 287.4,18.42
AC_IN1
  Top 0.61: J2.2 291.89,7.48 B1.AC1
AC_IN2
  Top 0.61: J2.1 292.14,2.38 B1.AC2
AGND  (via drill 0.25 pad 0.51)
  Top 0.152: C90.2 272.29,53.32 | C50.2 291.1,12.76 C1.- 286.79,11.2 286.69,11.3 C6.- 280.19,11.3 | 280.19,11.3 278.32,13.17 C7.2 | R34.2 275.84,51.23 v279.5,51.23 U$9.6 | 272.29,56.23 C92.2 | 272.66,76.62 v272.64,76.63 C56.2 | 268.94,56.23 C93.2 | 272.64,80.62 C59.2 | C57.2 269.14,78.06 | 280.19,11.3 280.19,2.59 279.97,2.38 B1.VSS | U$7.6 279.48,76.76 | 279.48,78.79 U$7.9 | v279.5,67.95 293.41,67.95 R2.2 293.43,67.16 R5.1
  Top 0.203: R34.2 275.81,52.09 274.7,52.09 274.7,52.88 274.27,53.31 C90.2 | 279.48,78.79 279.27,78.59 U$7.6 279.27,74.84 R32.2
  Top 0.508: C93.2 272.29,56.23 272.29,53.32 | C56.2 272.64,80.62 | 269.14,78.06 C58.2 C59.2 274.93,79.35 275.49,78.79 279.48,78.79 | U$9.9 279.7,55.52 | C92.2 274.27,56.28 275.03,55.52 279.7,55.52 | C57.2 266.4,78.06 | R39.1 266.02,78.06 266.4,78.06 | 266.4,78.06 C55.2 | R6.1 267.16,56.23 268.94,56.23 C91.2 267.81,53.39 C89.2 | 279.7,55.52 v281.99,55.52 | v289.05,55.52 U$13.A | U$7.9 279.91,79.5 v282.14,79.5 | v288.98,79.5 U$8.A
  Bottom 0.152: 279.81,23.24 279.5,23.55 v279.5,51.23 v279.5,67.95 272.64,67.95 v272.64,76.63 | C6.- 279.5,13.49 279.5,22.94 279.81,23.24 | 279.81,23.24 C28.-
  Bottom 0.508: v281.99,55.52 v289.05,55.52 | v282.14,79.5 v288.98,79.5
  other vias: 277.06,10.64 285.5,11.46 269.19,22.48 277.5,20.27 269.75,15.8 274.73,45.01 284.51,41.71 285.34,36.04 285.34,31.22 270.31,39.01 268.12,32.87 290.37,62.71 295.1,66.17 292.58,58.93 284.38,83.41 292.46,83.36 277.83,79.22 278.41,73.76 275.56,72.52 267.23,72.11 270.15,69.82 274.5,67.69 278.56,64.03 274.09,62.43 293.57,74.12 284.89,69.52 267.74,2.29 272.69,2.87 288.7,4.88 294.69,10.97
  pour Top (isolate 0.508): 265.71,85.85 297.71,85.85 297.71,0 265.71,0
  pour Bottom (isolate 0.508): 265.71,85.85 297.71,85.85 297.71,0 265.71,0
BOOT0  (via drill 0.25 pad 0.51)
  Top 0.152: v168.4,33.38 168.4,33.87 168.55,34.03 U1.166 | v154.79,12.17 168.28,12.17 169.09,11.35 R11.2
  Bottom 0.152: v154.79,12.17 154.79,27.03 156.39,28.63 157.15,28.63 157.96,27.81 157.96,19.03 158.17,18.82 162.18,18.82 162.38,19.03 162.38,33.38 162.59,33.58 168.2,33.58 v168.4,33.38
BUZZER  (via drill 0.25 pad 0.51)
  Top 0.152: v235.03,73.43 235.03,65.15 | 235.03,65.15 235.84,64.34 R43.2 | 235.03,65.15 234.01,66.17 234.01,66.32 230.84,69.49 229.13,69.49 228.93,69.29 228.93,64.59 227.33,62.99 183.21,62.99 180.04,59.82 180.04,57.25 180.87,56.41 180.87,54.48 180.48,54.09 U1.115
  Bottom 0.152: v235.03,73.43 234.54,73.91
CLK
  Top 0.152: Y1.3 214.82,10.59 R14.2
CLK1
  Top 0.152: Y2.3 167.55,16.18 R13.2
CLK_24MHZ  (via drill 0.25 pad 0.51)
  Top 0.152: v185.98,24.49 U1.29 | v185.98,14.55 209.94,14.55 213.12,11.38 R14.1
  Bottom 0.152: v185.98,14.55 v185.98,24.49
CLK_RTC  (via drill 0.25 pad 0.51)  (1 unrouted)
  Top 0.152: v179.17,15.93 179.12,15.88 R13.1 | v179.17,20.85 177.58,20.85 175.98,22.45 175.98,23.57 | 175.98,23.57 U1.9 | U1.4 173.48,25.09 173.25,24.87 173.25,23.88 173.58,23.55 175.98,23.57
  Bottom 0.152: v179.17,20.85 v179.17,15.93
CS  (via drill 0.25 pad 0.51)
  Top 0.152: RN11.5 160.39,75.54 161.2,74.74 U$19.P2 175.3,74.74 v175.97,74.07 | v175.49,28.83 175.48,28.82 U1.8
  Bottom 0.152: v175.49,28.83 175.49,48.49 175.97,48.97 v175.97,74.07
D0  (via drill 0.25 pad 0.51)
  Top 0.152: v203,39.98 203,29.13 204.6,27.53 208.4,27.53 RN4.8 | v187.86,48.23 185.98,50.12 U1.104
  Bottom 0.152: v187.86,48.23 v187.85,48.23 187.85,47.28 188.26,46.86 190.5,46.86 195.28,42.09 202.59,42.09 203,41.68 v203,39.98
D1  (via drill 0.25 pad 0.51)
  Top 0.152: v185.83,47.32 185.55,47.6 185.55,50.98 185.48,51.05 U1.105 | v209.19,27.13 v209.2,27.13 RN4.7
  Bottom 0.152: v209.19,27.13 196.22,27.13 193.5,29.84 187.43,29.84 185.83,31.45 v185.83,47.32
D2  (via drill 0.25 pad 0.51)
  Top 0.152: v187.55,45.87 187.4,46.03 U1.142 | v210.01,27.13 v210,27.13 RN4.6
  Bottom 0.152: v210.01,27.13 209.52,27.61 196.52,27.61 193.98,30.15 188.37,30.15 187.55,30.96 v187.55,45.87
D3  (via drill 0.25 pad 0.51)
  Top 0.152: v191.06,43.33 179.55,43.33 177.36,45.53 U1.143 | v202.03,28.8 202.03,28.25 203.63,26.65 210.39,26.65 210.8,27.05 RN4.5
  Bottom 0.152: v202.03,28.8 200.11,28.8 197.77,31.14 192.66,31.14 191.06,32.74 v191.06,43.33
D4  (via drill 0.25 pad 0.51)
  Top 0.152: v196.75,40.51 196.74,40.53 U1.68 | v206.17,38.23 206.17,30.61 207.77,29.01 211.46,29.01 211.61,28.85 211.61,28.41 212.01,28.01 RN3.8
  Bottom 0.152: v206.17,38.23 198.78,38.23 197.97,39.04 197.97,40.1 197.56,40.51 v196.75,40.51
D5  (via drill 0.25 pad 0.51)
  Top 0.152: v201.75,41.02 202.67,41.02 203.48,40.21 203.48,30.3 205.08,28.7 211.15,28.7 211.3,28.55 211.3,27.71 211.71,27.3 213.62,27.3 RN3.7 | v197.97,41.02 v197.96,41.03 U1.69
  Bottom 0.152: v197.97,41.02 v201.75,41.02
D6  (via drill 0.25 pad 0.51)
  Top 0.152: v212.75,28.88 214.27,28.88 214.42,28.73 RN3.6 | v194.13,39.9 194.13,41.32 194.34,41.53 U1.70
  Bottom 0.152: v194.13,39.9 195.81,39.9 198.63,37.08 200.69,37.08 204.83,32.94 209.58,32.94 212.75,29.77 v212.75,28.88
D7  (via drill 0.25 pad 0.51)
  Top 0.152: v197.05,41.53 197.05,42.62 196.65,43.03 U1.73 | v216.08,41.33 202.44,41.33 v202.23,41.53 | v216.08,28.7 215.22,28.7 RN3.5
  Bottom 0.152: v202.23,41.53 v197.05,41.53 | v216.08,28.7 v216.08,41.33
D8  (via drill 0.25 pad 0.51)
  Top 0.152: v196.75,43.54 196.74,43.53 U1.74 | v215.24,49.35 215.3,49.35 215.55,49.1 RN2.8
  Bottom 0.152: v215.24,49.35 215.24,46.71 212.06,43.54 v196.75,43.54
D9  (via drill 0.25 pad 0.51)
  Top 0.152: v198.07,43.05 197.1,44.03 U1.75 | v197.46,53.16 197.94,52.68 227.15,52.68 228.75,51.08 228.75,41.66 227.94,40.84 v207.9,40.84 | v198.2,49.35 198.2,49.91 198.6,50.32 213.94,50.32 214.75,49.51 RN2.7
  Bottom 0.152: v207.9,40.84 205.61,43.13 198.15,43.13 v198.07,43.05 | v198.2,49.35 198.2,52.43 v197.46,53.16
D10  (via drill 0.25 pad 0.51)
  Top 0.152: v211.53,49.35 213.8,49.35 213.95,49.2 RN2.6 | v196.75,44.53 | v196.75,44.53 U1.76
  Bottom 0.152: v196.75,44.53 208.36,44.53 211.53,47.7 v211.53,49.35
D11  (via drill 0.25 pad 0.51)
  Top 0.152: v194.16,44.98 194.75,44.98 194.79,45.03 U1.77 | v212.19,48.51 213.15,48.51 RN2.5
  Bottom 0.152: v212.19,48.51 212.19,47.19 209.02,44.02 195.12,44.02 v194.16,44.98
D12
  Top 0.152: RN1.8 210.83,47.68 198.83,47.68 197.23,46.08 197.23,45.75 197.01,45.53 U1.78
D13  (via drill 0.25 pad 0.51)
  Top 0.152: v198.81,49.84 209.62,49.84 210.03,49.43 RN1.7 | v198.81,56.59 190.79,56.59 189.98,55.78 U1.96
  Bottom 0.152: v198.81,56.59 v198.81,49.84
D14  (via drill 0.25 pad 0.51)
  Top 0.152: v191.29,51.21 189.63,51.21 189.48,51.36 U1.97 | v209.22,49.35 209.22,48.6 209.23,48.59 RN1.6
  Bottom 0.152: v209.22,49.35 205.97,46.1 204.3,46.1 202.7,47.7 202.7,57.95 199.52,61.14 197.69,61.14 194.51,57.96 194.51,53.06 193.7,52.25 192.33,52.25 v191.29,51.21
D15  (via drill 0.25 pad 0.51)
  Top 0.152: v188.98,48.16 188.98,51.84 U1.98 | v198.98,48.16 199.3,48.47 RN1.5
  Bottom 0.152: v198.98,48.16 v188.98,48.16
DAC1_OUT1
  Top 0.152: U$10.2 R64.1 R21.1 237.59,36.13 234.42,32.96 234.42,28.91 234.21,28.7 223.87,28.7 223.06,27.89 223.06,27.33 221.46,25.73 200.41,25.73 198.81,27.33 198.81,29.9 197.21,31.5 195.45,31.5 U1.50
DAC1_OUT2
  Top 0.152: U1.51 196.67,32.03 TP18.TP
FMC_NBL0  (via drill 0.25 pad 0.51)
  Top 0.152: v165.13,32.13 R71.1 | v166.83,32.51 167.01,32.33 168.5,32.33 168.7,32.53 U1.169
  Bottom 0.152: v166.83,32.51 165.51,32.51 v165.13,32.13
FMC_NBL1
  Top 0.152: R70.1 165.1,34.29 165.91,33.48 165.91,32.44 166.32,32.03 U1.170
GND  (via drill 0.25 pad 0.51, 4.06 pad 6.6)  (2 unrouted)
  Top 0.152: 248.57,67.4 T1.E | 235.64,70.27 237.55,68.48 v238.56,68.48 242.33,68.48 T1.E | R63.1 257.02,10.08 257.33,9.78 254.22,6.67 T4.E 244.06,6.8 R53.1 242.24,6.02 241.43,5.21 v240.03,5.21 | R63.1 259.13,19.95 260.74,21.57 C27.1 260.77,23.44 | R6.2 257.2,55.07 256.59,55.68 C11.- 253.85,55.68 253.28,56.25 C17.2 249.59,56.25 249.35,56.49 v248.87,56.49 245.69,53.31 v245.14,53.31 | C16.2 253.99,78.98 254.58,78.38 C3.- R39.2 | R63.1 R62.1 252.34,19.95 v252.32,19.96 250.09,19.96 IC1.3 | T1.E 242.28,67.4 C45.1 242.28,63.22 R35.1 242.3,62.32 242.09,62.1 238.51,62.1 v238.02,62.59 | R44.2 254.03,41.19 T7.E 253.11,41.29 253.11,40.59 v253.34,40.36 | U$1.2 257.81,71.27 257.4,70.87 v256.67,70.87 256.03,70.87 255.83,70.66 255.83,70.22 R61.2 254.24,70.22 253.82,69.8 253.82,69.77 C15.2 253.02,68.83 252.61,68.43 v250.72,68.43 | v252.78,38.76 R21.2 | v252.78,31.22 U$10.5 | v235.86,20.07 235.86,27.18 237.36,27.18 | R26.2 248.54,29.52 250.11,28.68 v251.28,28.68 | 237.36,27.18 241.45,27.18 241.45,24.51 U$17.2 244.25,24.51 244.25,25.1 v244.4,25.1 245.34,25.1 C30.2 245.34,25.98 244.91,26.42 244.91,27.89 245.11,28.09 247.04,28.09 v249.28,25.86 | v260.38,83.36 249,83.36 v248.97,83.39 | v244.58,67.31 245.75,66.14 v249.48,66.14 | v248.97,40.84 248.18,40.06 v244.12,40.06 | C37.- 252.58,15.11 253.39,14.3 v254.08,14.3 | T6.E 260.77,26.47 258.85,26.47 258.04,27.28 v258.04,28.42 | C29.2 233.51,55.74 v233.53,55.73 233.46,55.66 C26.2 | v231.06,83.34 232.18,83.34 232.56,83.72 v237.11,83.72 238.2,83.72 v241.15,80.77 | C51.1 231.47,70.5 231.79,70.81 v232.74,70.81 232.74,74.14 v231.44,75.44
  Top 0.152: C34.2 237.36,25.94 237.36,27.18 | v249.91,37.97 248.84,36.91 | v254.2,47.04 250.16,47.04 v249.25,47.95 | v241.25,73.03 244.4,73.03 v244.91,73.53 | 205.04,15.72 v197.87,15.72 196.89,15.72 196.08,16.54 R60.1 | 205.04,15.72 C2.2 | 198.07,72.1 C36.1 | v199.72,72.11 199.71,72.1 198.07,72.1 | 218.87,70.72 218.87,72.38 C60.1 218.01,72.38 218.01,74.12 217.45,74.12 U$5.1 | 218.87,70.72 C49.1 220.55,72.45 220.95,72.86 C62.1 | 208.4,42.65 208.88,42.16 v212.88,42.16 | 208.4,42.65 206.96,42.65 206.8,42.81 U$15.54 206.8,44.91 204.44,44.91 201.27,41.73 201.27,37.9 200.46,37.08 198.1,37.08 198.04,37.03 U1.61 194.16,37.03 193.37,37.82 193.37,41.4 | 217.2,42.16 227.1,42.16 v227.58,42.65 227.6,42.66 U$15.28 | 217.2,42.16 v212.88,42.16 | v146.66,64.77 163.93,64.77 C38.- 168.62,60.08 C9.2 | JP1.1 166.5,3.89 166.65,3.73 183.59,3.73 SV5.3 | 56.41,5.72 58.9,3.23 69.42,3.23 69.72,3.53 | 69.72,3.53 70.03,3.23 81.15,3.23 C40.- 85.34,4.62 85.69,4.97 C41.2 86.56,5.84 v94.51,5.84 | 188.95,47.14 188.65,46.84 v176.76,46.84 173.99,46.84 v171.96,48.87 172.75,49.66 174.96,49.66 | 193.37,41.4 193.07,41.71 v180.98,41.71 v176.76,41.71 | v146.63,9.75 157.1,9.75 157.32,9.54 C5.2 156.15,8.79 155.34,7.98 S1.1 | 217.2,42.16 U$15.41 | 189.97,30.38 189.66,30.68 182.09,30.68 181.94,30.53 v181.46,30.53 182.48,29.51 U1.22 | 205.04,15.72 C4.2 | v239.9,15.01 247.02,15.01 v247.04,15.04 | C31.2 208.79,58.17 208.99,57.96 v214.35,57.96 214.34,57.95 IC2.8 214.34,55.56 214.12,55.35 212.59,55.35 212.39,55.55 IC2.5 212.39,57.12 211.74,57.12 IC2.4 | C23.1 209.75,72.96 208.94,72.15 C47.1 207.21,70.85 C32.1 206.36,70.68 v206.35,70.66 206.35,72.4 206.5,72.55 C21.1
  Top 0.152: v229.62,20.47 230.12,20.47 v232.64,17.96 | 46.56,7.95 46.56,7.85 46.76,7.65 47.07,7.65 47.78,8.36 53.24,8.36 J1.36 53.24,6.53 54.05,5.72 56.41,5.72 | 46.56,7.95 R38.2 | 208.4,42.65 U$15.52 | v234.98,11.25 233.55,11.25 v231.95,9.65 231.47,9.17 222.71,9.17 C8.2 C12.2 219.52,10.07 219.3,10.29 219.3,10.59 Y1.2 | C42.2 C13.2 v230.2,42.01 | R55.1 231.5,30.48 v233.38,30.48 233.38,29.76 233.17,29.55 T5.E | T3.E 197.71,9.43 197.87,9.58 v197.87,10.39 197.87,11.35 R30.1 | 218.87,70.72 C33.1 218.02,70.53 v218.01,70.51 | 198.07,72.1 C52.1 | v199.72,72.11 C46.1 | v199.72,72.11 200.66,72.11 C20.1 | v230.15,36.22 C14.2 | C63.1 v228.24,71.4 | v228.24,71.4 C35.1 | 46.56,7.95 32.82,7.95 32.62,7.75 J3.2 32.62,5.23 32.46,5.08 v31.83,5.08 | v228.24,71.4 227,71.4 226.8,71.6 U$6.1 | 175.29,83.41 175.29,79.14 U$19.P6 174.04,79.14 174.03,79.15 v172.03,79.15 | 175.29,83.41 175.59,83.72 U$19.G3 | 175.29,83.41 174.98,83.72 U$19.G4 | 69.72,3.53 69.72,7.15 69.74,7.16 J1.3 69.74,8.36 70.74,8.36 J1.1 | 56.41,5.72 56.74,6.04 J1.29 | v212.88,42.16 212.88,42.65 213.04,42.65 213.2,42.8 U$15.46 | 174.96,49.66 175.26,49.35 179.88,49.35 181.48,50.95 U1.113 | 188.95,47.14 189.8,47.14 192.98,50.32 U1.90 | 188.95,47.14 188.34,47.75 188.34,49.38 186.98,50.74 U1.102 | 189.97,30.38 190.27,30.68 192,30.68 192.16,30.53 U1.48 | 189.97,30.38 189.97,30.25 189.98,30.25 U1.37 | v176.76,28.96 178.07,28.96 178.48,28.55 U1.14 | 174.96,49.66 174.96,51.82 174.98,51.84 U1.126 | 193.37,41.4 193.99,42.03 U1.71 | v211.63,34.16 210.95,34.16 210.8,34.01 U$15.6 | v215.6,34.65 U$15.12 | v171.3,43.03 U1.148 | v191.44,71.25 C48.1 | v208.79,55.63 208.53,55.37 C10.2
  Top 0.152: v172.54,72.57 178.4,72.57 180,70.97 U$19.G2 | v171.12,51.08 171.12,49.53 U1.135 | v171.3,40.46 171.3,38.18 171.15,38.03 U1.158 | Y2.2 v162.81,16.18 162.81,16.37 162.56,16.62 C25.2 C24.2 | v205.74,71.63 U$4.1 | v196.67,71.35 U$3.1 | v150.19,75.21 X5.5 | v171.7,71.12 U$19.G1
  Top 0.203: C30.2 | 252.34,19.95 252.34,16.62 C37.-
  Top 0.254: 260.77,23.44 T6.E
  Top 0.406: 261.98,64.77 v261.98,64.59 | C18.2 263.25,67.72 263.25,64.77
  Top 1.016: 257.33,9.78 v268.83,9.78 | v268.83,64.77 263.25,64.77 261.98,64.77
  Bottom 0.152: C11.- 255.75,47.04 | 255.75,47.04 255.75,42.77 v253.34,40.36 253.34,39.32 v252.78,38.76 252.78,37.97 | C11.- 256.9,56.82 256.9,61.8 | 256.9,61.8 256.9,64.77 256.59,65.08 256.59,70.79 v256.67,70.87 255.83,71.7 255.83,74.6 | C3.- 255.83,74.6 | 252.78,33.71 v252.78,31.22 252.78,29.52 252.32,29.06 252.32,28.63 | 252.78,33.71 252.78,36.96 | 252.78,36.96 252.78,37.97 | 252.32,28.63 252.32,25.86 | 252.32,25.86 v252.32,19.96 | v251.28,28.68 252.27,28.68 arc-90 252.32,28.63 | 238.25,67.41 238.56,67.11 v238.56,58.17 235.97,58.17 v233.53,55.73 233.53,54.66 | v241.25,73.03 241.25,71.17 v238.56,68.48 238.56,67.72 238.25,67.41 | v261.92,50.9 261.92,54.05 v260.32,55.65 260.3,55.68 C11.- | v260.38,83.36 260.38,81.46 260.15,81.23 v260.15,77.57 260.15,74.91 | v259.99,20.68 259.99,15.29 v260.02,15.27 259.94,15.19 259.94,2.77 v260.43,2.29 | v254.08,14.3 252.96,13.18 v252.96,10.03 | 256.9,61.8 v261.87,61.8 261.87,63.6 261.98,63.7 v261.98,64.59 261.98,65.08 262.1,65.2 v260.35,66.06 | v258.04,28.42 262.26,28.42 262.56,28.73 | 255.83,74.6 259.84,74.6 260.15,74.91 | 262.56,28.73 v262.56,32.61 | v248.97,40.84 248.97,38.91 v249.91,37.97 252.78,37.97 | v250.72,68.43 250.72,67.39 v249.48,66.14 | 262.56,28.73 263.07,28.22 v263.07,25.45 | 252.32,25.86 v249.28,25.86 | v249.28,25.86 | 252.78,33.71 v250.09,33.71 | 260.15,74.91 260.45,74.6 v262.48,74.6 | 238.25,67.41 v236.86,67.41 232.82,71.45 232.56,71.45 232.26,71.14 | 255.75,47.04 v254.2,47.04 | v254.2,47.04 | 233.53,54.66 233.53,54.63 233.32,54.63 | v231.06,83.34 231.06,77.98 231.44,77.6 v231.44,75.44 231.44,74.6 v228.24,71.4 226.31,71.4 225.43,70.51 | 252.78,36.96 v258.78,36.96 259.99,36.96 v262.31,39.27
  Bottom 0.152: v232.74,70.81 232.74,70.33 | 232.74,70.33 232.74,70.26 232.84,70.16 232.84,65.66 | 232.84,65.66 232.84,65.51 | 232.26,71.14 231.95,71.45 | 232.74,70.33 232.46,70.33 232.26,70.54 232.26,71.14 | 234.98,15.01 v234.98,11.25 232.08,11.25 | 234.98,15.01 234.98,17.96 | 234.98,17.96 234.98,18.29 | 234.98,18.29 234.98,20.07 | 234.98,20.07 234.98,21.67 234.52,22.12 234.52,27 233.91,27.61 233.91,28.3 234.52,28.91 | 231.5,65.18 v232.44,65.18 232.44,65.66 232.84,65.66 | 233.53,54.66 236.63,54.66 v238.48,52.81 238.48,51.23 v236.3,49.05 233.15,45.9 v231.42,45.9 230.2,44.68 v230.2,42.01 | v146.63,9.75 115.27,9.75 113.72,11.3 v94.51,11.3 v94.51,5.84 | SV5.3 183.59,7.24 196.27,7.24 197.87,8.84 v197.87,10.39 v197.87,15.72 | v146.63,9.75 164.54,9.75 164.85,10.06 | 171.12,62.05 v171.12,51.08 171.12,49.71 v171.96,48.87 171.96,43.69 v171.3,43.03 v171.3,40.46 | 171.12,62.05 171.7,62.64 v171.7,71.12 172.54,71.96 v172.54,72.57 172.03,73.08 v172.03,79.15 | 225.43,70.51 225.73,70.21 C39.- 217.55,61.16 v214.35,57.96 211.12,57.96 v208.79,55.63 | 225.43,70.51 v218.01,70.51 215.52,70.51 215.37,70.66 v206.35,70.66 206.35,71.63 v205.74,71.63 205.26,72.11 v199.72,72.11 197.43,72.11 v196.67,71.35 191.54,71.35 v191.44,71.25 | v212.88,42.16 212.88,34.95 212.57,34.65 | v244.4,21.44 v244.4,25.1 244.4,30.45 v245.06,31.12 245.03,31.14 v245.03,34.75 | v243.31,2.44 244.88,2.44 v247.37,4.93 247.37,9.96 v246.61,10.72 246.61,13.97 247.04,14.4 v247.04,15.04 | JP1.1 166.5,8.41 164.85,10.06 | v239.9,15.01 234.98,15.01 | v248.87,56.49 248.87,53.14 v249.4,52.6 | C38.- 170.82,62.36 171.12,62.05 | 236.4,28.91 v236.4,32.56
  Bottom 0.152: v245.14,53.31 245.14,55.93 244.88,56.19 v244.88,56.84 | v231.95,9.65 v231.95,6.66 | 234.98,18.29 v237.64,18.29 | v229.62,20.47 232.11,22.96 v232.11,26.62 | v232.64,17.96 234.98,17.96 | 234.52,28.91 234.82,28.6 236.09,28.6 236.4,28.91 | 236.4,28.91 236.7,28.6 v237.87,28.6 | 234.52,28.91 234.52,29.34 v233.38,30.48 | v230.2,42.01 230.68,41.53 230.68,36.75 v230.15,36.22 | v235.86,20.07 | v235.86,20.07 234.98,20.07 | v146.63,9.75 146.63,21.72 146.96,22.05 SV1.20 SV1.18 SV1.16 SV1.14 SV1.12 SV1.10 SV1.8 SV1.6 SV1.4 145.97,51.38 145.97,58.17 146.66,58.85 v146.66,64.77 150.19,68.3 v150.19,75.21 | v31.83,5.08 12.6,5.08 v6.38,11.3 | v176.76,46.84 v176.76,41.71 v176.76,28.96 | v162.81,16.18 164.85,14.15 164.85,10.06 | v227.58,42.65 228.22,42.01 v230.2,42.01 | 212.57,34.65 211.63,34.65 211.63,34.42 211.63,34.41 v211.63,34.16 | 212.57,34.65 v215.6,34.65 | v181.46,30.53 180.98,31.01 v180.98,41.71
